VERSION 5.8 ;
BUSBITCHARS "[]" ;
DIVIDERCHAR "/" ;
UNITS
    DATABASE MICRONS 1000 ;
END UNITS

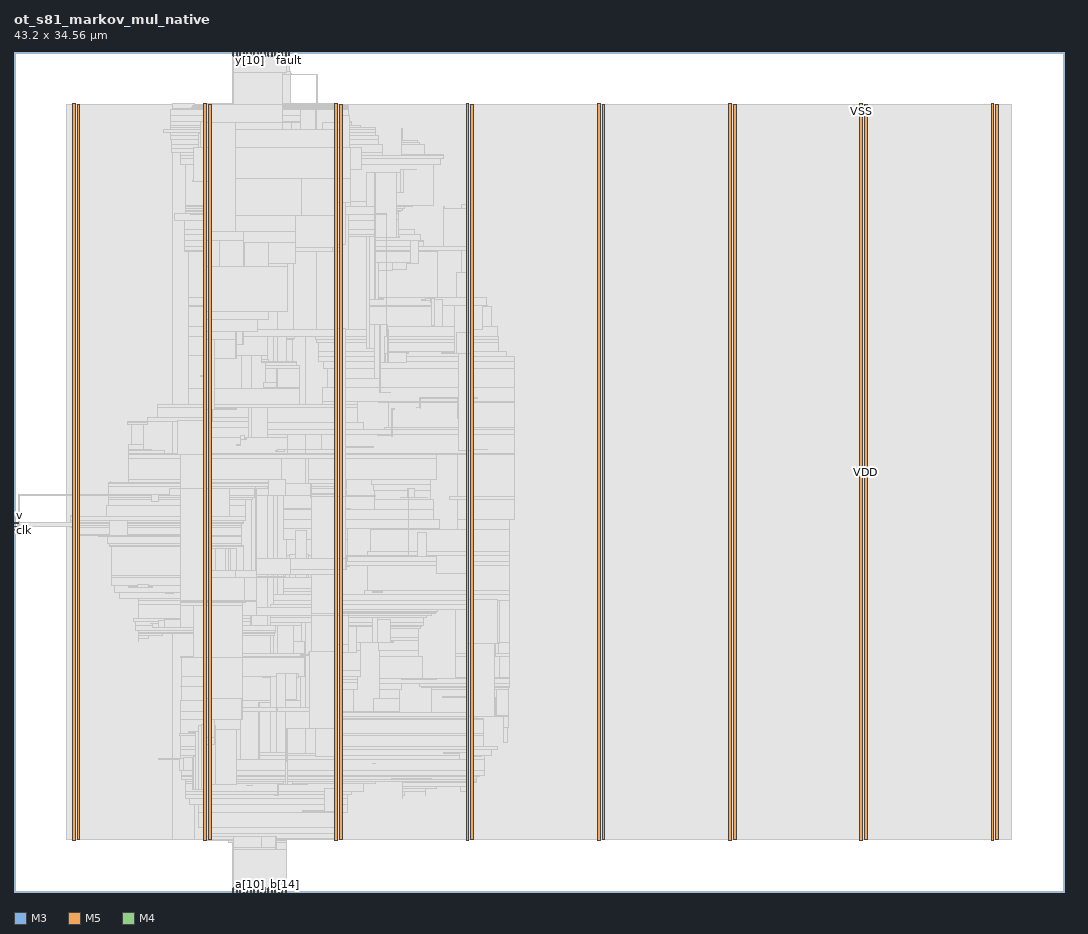
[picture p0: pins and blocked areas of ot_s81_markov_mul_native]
MACRO ot_s81_markov_mul_native
  FOREIGN ot_s81_markov_mul_native 0 0 ;
  CLASS BLOCK ;
  SIZE 43.2 BY 34.56 ;
  PIN a[0]
    DIRECTION INPUT ;
    USE SIGNAL ;
    PORT
      LAYER M3 ;
        RECT  9 0 9.018 0.144 ;
    END
  END a[0]
  PIN a[10]
    DIRECTION INPUT ;
    USE SIGNAL ;
    PORT
      LAYER M3 ;
        RECT  9.72 0 9.738 0.144 ;
    END
  END a[10]
  PIN a[11]
    DIRECTION INPUT ;
    USE SIGNAL ;
    PORT
      LAYER M5 ;
        RECT  9.744 0 9.768 0.192 ;
    END
  END a[11]
  PIN a[12]
    DIRECTION INPUT ;
    USE SIGNAL ;
    PORT
      LAYER M3 ;
        RECT  9.864 0 9.882 0.144 ;
    END
  END a[12]
  PIN a[13]
    DIRECTION INPUT ;
    USE SIGNAL ;
    PORT
      LAYER M5 ;
        RECT  9.888 0 9.912 0.192 ;
    END
  END a[13]
  PIN a[14]
    DIRECTION INPUT ;
    USE SIGNAL ;
    PORT
      LAYER M3 ;
        RECT  10.008 0 10.026 0.144 ;
    END
  END a[14]
  PIN a[15]
    DIRECTION INPUT ;
    USE SIGNAL ;
    PORT
      LAYER M5 ;
        RECT  10.032 0 10.056 0.192 ;
    END
  END a[15]
  PIN a[1]
    DIRECTION INPUT ;
    USE SIGNAL ;
    PORT
      LAYER M5 ;
        RECT  9.024 0 9.048 0.192 ;
    END
  END a[1]
  PIN a[2]
    DIRECTION INPUT ;
    USE SIGNAL ;
    PORT
      LAYER M3 ;
        RECT  9.144 0 9.162 0.144 ;
    END
  END a[2]
  PIN a[3]
    DIRECTION INPUT ;
    USE SIGNAL ;
    PORT
      LAYER M5 ;
        RECT  9.168 0 9.192 0.192 ;
    END
  END a[3]
  PIN a[4]
    DIRECTION INPUT ;
    USE SIGNAL ;
    PORT
      LAYER M3 ;
        RECT  9.288 0 9.306 0.144 ;
    END
  END a[4]
  PIN a[5]
    DIRECTION INPUT ;
    USE SIGNAL ;
    PORT
      LAYER M5 ;
        RECT  9.312 0 9.336 0.192 ;
    END
  END a[5]
  PIN a[6]
    DIRECTION INPUT ;
    USE SIGNAL ;
    PORT
      LAYER M3 ;
        RECT  9.432 0 9.45 0.144 ;
    END
  END a[6]
  PIN a[7]
    DIRECTION INPUT ;
    USE SIGNAL ;
    PORT
      LAYER M5 ;
        RECT  9.456 0 9.48 0.192 ;
    END
  END a[7]
  PIN a[8]
    DIRECTION INPUT ;
    USE SIGNAL ;
    PORT
      LAYER M3 ;
        RECT  9.576 0 9.594 0.144 ;
    END
  END a[8]
  PIN a[9]
    DIRECTION INPUT ;
    USE SIGNAL ;
    PORT
      LAYER M5 ;
        RECT  9.6 0 9.624 0.192 ;
    END
  END a[9]
  PIN b[0]
    DIRECTION INPUT ;
    USE SIGNAL ;
    PORT
      LAYER M3 ;
        RECT  10.152 0 10.17 0.144 ;
    END
  END b[0]
  PIN b[10]
    DIRECTION INPUT ;
    USE SIGNAL ;
    PORT
      LAYER M3 ;
        RECT  10.872 0 10.89 0.144 ;
    END
  END b[10]
  PIN b[11]
    DIRECTION INPUT ;
    USE SIGNAL ;
    PORT
      LAYER M5 ;
        RECT  10.896 0 10.92 0.192 ;
    END
  END b[11]
  PIN b[12]
    DIRECTION INPUT ;
    USE SIGNAL ;
    PORT
      LAYER M3 ;
        RECT  11.016 0 11.034 0.144 ;
    END
  END b[12]
  PIN b[13]
    DIRECTION INPUT ;
    USE SIGNAL ;
    PORT
      LAYER M5 ;
        RECT  11.04 0 11.064 0.192 ;
    END
  END b[13]
  PIN b[14]
    DIRECTION INPUT ;
    USE SIGNAL ;
    PORT
      LAYER M3 ;
        RECT  11.16 0 11.178 0.144 ;
    END
  END b[14]
  PIN b[15]
    DIRECTION INPUT ;
    USE SIGNAL ;
    PORT
      LAYER M5 ;
        RECT  11.184 0 11.208 0.192 ;
    END
  END b[15]
  PIN b[1]
    DIRECTION INPUT ;
    USE SIGNAL ;
    PORT
      LAYER M5 ;
        RECT  10.176 0 10.2 0.192 ;
    END
  END b[1]
  PIN b[2]
    DIRECTION INPUT ;
    USE SIGNAL ;
    PORT
      LAYER M3 ;
        RECT  10.296 0 10.314 0.144 ;
    END
  END b[2]
  PIN b[3]
    DIRECTION INPUT ;
    USE SIGNAL ;
    PORT
      LAYER M5 ;
        RECT  10.32 0 10.344 0.192 ;
    END
  END b[3]
  PIN b[4]
    DIRECTION INPUT ;
    USE SIGNAL ;
    PORT
      LAYER M3 ;
        RECT  10.44 0 10.458 0.144 ;
    END
  END b[4]
  PIN b[5]
    DIRECTION INPUT ;
    USE SIGNAL ;
    PORT
      LAYER M5 ;
        RECT  10.464 0 10.488 0.192 ;
    END
  END b[5]
  PIN b[6]
    DIRECTION INPUT ;
    USE SIGNAL ;
    PORT
      LAYER M3 ;
        RECT  10.584 0 10.602 0.144 ;
    END
  END b[6]
  PIN b[7]
    DIRECTION INPUT ;
    USE SIGNAL ;
    PORT
      LAYER M5 ;
        RECT  10.608 0 10.632 0.192 ;
    END
  END b[7]
  PIN b[8]
    DIRECTION INPUT ;
    USE SIGNAL ;
    PORT
      LAYER M3 ;
        RECT  10.728 0 10.746 0.144 ;
    END
  END b[8]
  PIN b[9]
    DIRECTION INPUT ;
    USE SIGNAL ;
    PORT
      LAYER M5 ;
        RECT  10.752 0 10.776 0.192 ;
    END
  END b[9]
  PIN clk
    DIRECTION INPUT ;
    USE SIGNAL ;
    PORT
      LAYER M4 ;
        RECT  0 14.88 0.192 14.904 ;
    END
  END clk
  PIN fault
    DIRECTION OUTPUT ;
    USE SIGNAL ;
    PORT
      LAYER M3 ;
        RECT  11.304 34.416 11.322 34.56 ;
    END
  END fault
  PIN rst_n
    DIRECTION INPUT ;
    USE SIGNAL ;
    PORT
      LAYER M4 ;
        RECT  0 15.024 0.192 15.048 ;
    END
  END rst_n
  PIN v
    DIRECTION INPUT ;
    USE SIGNAL ;
    PORT
      LAYER M4 ;
        RECT  0 15.168 0.192 15.192 ;
    END
  END v
  PIN y[0]
    DIRECTION OUTPUT ;
    USE SIGNAL ;
    PORT
      LAYER M3 ;
        RECT  9 34.416 9.018 34.56 ;
    END
  END y[0]
  PIN y[10]
    DIRECTION OUTPUT ;
    USE SIGNAL ;
    PORT
      LAYER M3 ;
        RECT  9.72 34.416 9.738 34.56 ;
    END
  END y[10]
  PIN y[11]
    DIRECTION OUTPUT ;
    USE SIGNAL ;
    PORT
      LAYER M5 ;
        RECT  9.744 34.368 9.768 34.56 ;
    END
  END y[11]
  PIN y[12]
    DIRECTION OUTPUT ;
    USE SIGNAL ;
    PORT
      LAYER M3 ;
        RECT  9.864 34.416 9.882 34.56 ;
    END
  END y[12]
  PIN y[13]
    DIRECTION OUTPUT ;
    USE SIGNAL ;
    PORT
      LAYER M5 ;
        RECT  9.888 34.368 9.912 34.56 ;
    END
  END y[13]
  PIN y[14]
    DIRECTION OUTPUT ;
    USE SIGNAL ;
    PORT
      LAYER M3 ;
        RECT  10.008 34.416 10.026 34.56 ;
    END
  END y[14]
  PIN y[15]
    DIRECTION OUTPUT ;
    USE SIGNAL ;
    PORT
      LAYER M5 ;
        RECT  10.032 34.368 10.056 34.56 ;
    END
  END y[15]
  PIN y[16]
    DIRECTION OUTPUT ;
    USE SIGNAL ;
    PORT
      LAYER M3 ;
        RECT  10.152 34.416 10.17 34.56 ;
    END
  END y[16]
  PIN y[17]
    DIRECTION OUTPUT ;
    USE SIGNAL ;
    PORT
      LAYER M5 ;
        RECT  10.176 34.368 10.2 34.56 ;
    END
  END y[17]
  PIN y[18]
    DIRECTION OUTPUT ;
    USE SIGNAL ;
    PORT
      LAYER M3 ;
        RECT  10.296 34.416 10.314 34.56 ;
    END
  END y[18]
  PIN y[19]
    DIRECTION OUTPUT ;
    USE SIGNAL ;
    PORT
      LAYER M5 ;
        RECT  10.32 34.368 10.344 34.56 ;
    END
  END y[19]
  PIN y[1]
    DIRECTION OUTPUT ;
    USE SIGNAL ;
    PORT
      LAYER M5 ;
        RECT  9.024 34.368 9.048 34.56 ;
    END
  END y[1]
  PIN y[20]
    DIRECTION OUTPUT ;
    USE SIGNAL ;
    PORT
      LAYER M3 ;
        RECT  10.44 34.416 10.458 34.56 ;
    END
  END y[20]
  PIN y[21]
    DIRECTION OUTPUT ;
    USE SIGNAL ;
    PORT
      LAYER M5 ;
        RECT  10.464 34.368 10.488 34.56 ;
    END
  END y[21]
  PIN y[22]
    DIRECTION OUTPUT ;
    USE SIGNAL ;
    PORT
      LAYER M3 ;
        RECT  10.584 34.416 10.602 34.56 ;
    END
  END y[22]
  PIN y[23]
    DIRECTION OUTPUT ;
    USE SIGNAL ;
    PORT
      LAYER M5 ;
        RECT  10.608 34.368 10.632 34.56 ;
    END
  END y[23]
  PIN y[24]
    DIRECTION OUTPUT ;
    USE SIGNAL ;
    PORT
      LAYER M3 ;
        RECT  10.728 34.416 10.746 34.56 ;
    END
  END y[24]
  PIN y[25]
    DIRECTION OUTPUT ;
    USE SIGNAL ;
    PORT
      LAYER M5 ;
        RECT  10.752 34.368 10.776 34.56 ;
    END
  END y[25]
  PIN y[26]
    DIRECTION OUTPUT ;
    USE SIGNAL ;
    PORT
      LAYER M3 ;
        RECT  10.872 34.416 10.89 34.56 ;
    END
  END y[26]
  PIN y[27]
    DIRECTION OUTPUT ;
    USE SIGNAL ;
    PORT
      LAYER M5 ;
        RECT  10.896 34.368 10.92 34.56 ;
    END
  END y[27]
  PIN y[28]
    DIRECTION OUTPUT ;
    USE SIGNAL ;
    PORT
      LAYER M3 ;
        RECT  11.016 34.416 11.034 34.56 ;
    END
  END y[28]
  PIN y[29]
    DIRECTION OUTPUT ;
    USE SIGNAL ;
    PORT
      LAYER M5 ;
        RECT  11.04 34.368 11.064 34.56 ;
    END
  END y[29]
  PIN y[2]
    DIRECTION OUTPUT ;
    USE SIGNAL ;
    PORT
      LAYER M3 ;
        RECT  9.144 34.416 9.162 34.56 ;
    END
  END y[2]
  PIN y[30]
    DIRECTION OUTPUT ;
    USE SIGNAL ;
    PORT
      LAYER M3 ;
        RECT  11.16 34.416 11.178 34.56 ;
    END
  END y[30]
  PIN y[31]
    DIRECTION OUTPUT ;
    USE SIGNAL ;
    PORT
      LAYER M5 ;
        RECT  11.184 34.368 11.208 34.56 ;
    END
  END y[31]
  PIN y[3]
    DIRECTION OUTPUT ;
    USE SIGNAL ;
    PORT
      LAYER M5 ;
        RECT  9.168 34.368 9.192 34.56 ;
    END
  END y[3]
  PIN y[4]
    DIRECTION OUTPUT ;
    USE SIGNAL ;
    PORT
      LAYER M3 ;
        RECT  9.288 34.416 9.306 34.56 ;
    END
  END y[4]
  PIN y[5]
    DIRECTION OUTPUT ;
    USE SIGNAL ;
    PORT
      LAYER M5 ;
        RECT  9.312 34.368 9.336 34.56 ;
    END
  END y[5]
  PIN y[6]
    DIRECTION OUTPUT ;
    USE SIGNAL ;
    PORT
      LAYER M3 ;
        RECT  9.432 34.416 9.45 34.56 ;
    END
  END y[6]
  PIN y[7]
    DIRECTION OUTPUT ;
    USE SIGNAL ;
    PORT
      LAYER M5 ;
        RECT  9.456 34.368 9.48 34.56 ;
    END
  END y[7]
  PIN y[8]
    DIRECTION OUTPUT ;
    USE SIGNAL ;
    PORT
      LAYER M3 ;
        RECT  9.576 34.416 9.594 34.56 ;
    END
  END y[8]
  PIN y[9]
    DIRECTION OUTPUT ;
    USE SIGNAL ;
    PORT
      LAYER M5 ;
        RECT  9.6 34.368 9.624 34.56 ;
    END
  END y[9]
  PIN VDD
    DIRECTION INOUT ;
    USE POWER ;
    PORT
      LAYER M5 ;
        RECT  40.392 2.151 40.512 32.409 ;
        RECT  34.992 2.151 35.112 32.409 ;
        RECT  29.592 2.151 29.712 32.409 ;
        RECT  24.192 2.151 24.312 32.409 ;
        RECT  18.792 2.151 18.912 32.409 ;
        RECT  13.392 2.151 13.512 32.409 ;
        RECT  7.992 2.151 8.112 32.409 ;
        RECT  2.592 2.151 2.712 32.409 ;
    END
  END VDD
  PIN VSS
    DIRECTION INOUT ;
    USE GROUND ;
    PORT
      LAYER M5 ;
        RECT  40.2 2.137 40.32 32.423 ;
        RECT  34.8 2.137 34.92 32.423 ;
        RECT  29.4 2.137 29.52 32.423 ;
        RECT  24 2.137 24.12 32.423 ;
        RECT  18.6 2.137 18.72 32.423 ;
        RECT  13.2 2.137 13.32 32.423 ;
        RECT  7.8 2.137 7.92 32.423 ;
        RECT  2.4 2.137 2.52 32.423 ;
    END
  END VSS
  # OT_OBS_CLOSED layer=M5 d_um=1.536 added=25
  OBS
    LAYER RVTN ;
     RECT  2.16 2.16 41.04 2.295 ;
     RECT  2.16 2.565 41.04 2.835 ;
     RECT  2.16 3.105 41.04 3.375 ;
     RECT  2.16 3.645 41.04 3.915 ;
     RECT  2.16 4.185 41.04 4.455 ;
     RECT  2.16 4.725 41.04 4.995 ;
     RECT  2.16 5.265 41.04 5.535 ;
     RECT  2.16 5.805 41.04 6.075 ;
     RECT  2.16 6.345 41.04 6.615 ;
     RECT  2.16 6.885 41.04 7.155 ;
     RECT  2.16 7.425 41.04 7.695 ;
     RECT  2.16 7.965 41.04 8.235 ;
     RECT  2.16 8.505 41.04 8.775 ;
     RECT  2.16 9.045 41.04 9.315 ;
     RECT  2.16 9.585 41.04 9.855 ;
     RECT  2.16 10.125 41.04 10.395 ;
     RECT  2.16 10.665 41.04 10.935 ;
     RECT  2.16 11.205 41.04 11.475 ;
     RECT  2.16 11.745 41.04 12.015 ;
     RECT  2.16 12.285 41.04 12.555 ;
     RECT  2.16 12.825 41.04 13.095 ;
     RECT  2.16 13.365 41.04 13.635 ;
     RECT  2.16 13.905 41.04 14.175 ;
     RECT  2.16 14.445 41.04 14.715 ;
     RECT  2.16 14.985 41.04 15.255 ;
     RECT  2.16 15.525 41.04 15.795 ;
     RECT  2.16 16.065 41.04 16.335 ;
     RECT  2.16 16.605 41.04 16.875 ;
     RECT  2.16 17.145 41.04 17.415 ;
     RECT  2.16 17.685 41.04 17.955 ;
     RECT  2.16 18.225 41.04 18.495 ;
     RECT  2.16 18.765 41.04 19.035 ;
     RECT  2.16 19.305 41.04 19.575 ;
     RECT  2.16 19.845 41.04 20.115 ;
     RECT  2.16 20.385 41.04 20.655 ;
     RECT  2.16 20.925 41.04 21.195 ;
     RECT  2.16 21.465 41.04 21.735 ;
     RECT  2.16 22.005 41.04 22.275 ;
     RECT  2.16 22.545 41.04 22.815 ;
     RECT  2.16 23.085 41.04 23.355 ;
     RECT  2.16 23.625 41.04 23.895 ;
     RECT  2.16 24.165 41.04 24.435 ;
     RECT  2.16 24.705 41.04 24.975 ;
     RECT  2.16 25.245 41.04 25.515 ;
     RECT  2.16 25.785 41.04 26.055 ;
     RECT  2.16 26.325 41.04 26.595 ;
     RECT  2.16 26.865 41.04 27.135 ;
     RECT  2.16 27.405 41.04 27.675 ;
     RECT  2.16 27.945 41.04 28.215 ;
     RECT  2.16 28.485 41.04 28.755 ;
     RECT  2.16 29.025 41.04 29.295 ;
     RECT  2.16 29.565 41.04 29.835 ;
     RECT  2.16 30.105 41.04 30.375 ;
     RECT  2.16 30.645 41.04 30.915 ;
     RECT  2.16 31.185 41.04 31.455 ;
     RECT  2.16 31.725 41.04 31.995 ;
     RECT  2.16 32.265 41.04 32.4 ;
    LAYER RVTP ;
     RECT  2.16 2.295 41.04 2.565 ;
     RECT  2.16 2.835 41.04 3.105 ;
     RECT  2.16 3.375 41.04 3.645 ;
     RECT  2.16 3.915 41.04 4.185 ;
     RECT  2.16 4.455 41.04 4.725 ;
     RECT  2.16 4.995 41.04 5.265 ;
     RECT  2.16 5.535 41.04 5.805 ;
     RECT  2.16 6.075 41.04 6.345 ;
     RECT  2.16 6.615 41.04 6.885 ;
     RECT  2.16 7.155 41.04 7.425 ;
     RECT  2.16 7.695 41.04 7.965 ;
     RECT  2.16 8.235 41.04 8.505 ;
     RECT  2.16 8.775 41.04 9.045 ;
     RECT  2.16 9.315 41.04 9.585 ;
     RECT  2.16 9.855 41.04 10.125 ;
     RECT  2.16 10.395 41.04 10.665 ;
     RECT  2.16 10.935 41.04 11.205 ;
     RECT  2.16 11.475 41.04 11.745 ;
     RECT  2.16 12.015 41.04 12.285 ;
     RECT  2.16 12.555 41.04 12.825 ;
     RECT  2.16 13.095 41.04 13.365 ;
     RECT  2.16 13.635 41.04 13.905 ;
     RECT  2.16 14.175 41.04 14.445 ;
     RECT  2.16 14.715 41.04 14.985 ;
     RECT  2.16 15.255 41.04 15.525 ;
     RECT  2.16 15.795 41.04 16.065 ;
     RECT  2.16 16.335 41.04 16.605 ;
     RECT  2.16 16.875 41.04 17.145 ;
     RECT  2.16 17.415 41.04 17.685 ;
     RECT  2.16 17.955 41.04 18.225 ;
     RECT  2.16 18.495 41.04 18.765 ;
     RECT  2.16 19.035 41.04 19.305 ;
     RECT  2.16 19.575 41.04 19.845 ;
     RECT  2.16 20.115 41.04 20.385 ;
     RECT  2.16 20.655 41.04 20.925 ;
     RECT  2.16 21.195 41.04 21.465 ;
     RECT  2.16 21.735 41.04 22.005 ;
     RECT  2.16 22.275 41.04 22.545 ;
     RECT  2.16 22.815 41.04 23.085 ;
     RECT  2.16 23.355 41.04 23.625 ;
     RECT  2.16 23.895 41.04 24.165 ;
     RECT  2.16 24.435 41.04 24.705 ;
     RECT  2.16 24.975 41.04 25.245 ;
     RECT  2.16 25.515 41.04 25.785 ;
     RECT  2.16 26.055 41.04 26.325 ;
     RECT  2.16 26.595 41.04 26.865 ;
     RECT  2.16 27.135 41.04 27.405 ;
     RECT  2.16 27.675 41.04 27.945 ;
     RECT  2.16 28.215 41.04 28.485 ;
     RECT  2.16 28.755 41.04 29.025 ;
     RECT  2.16 29.295 41.04 29.565 ;
     RECT  2.16 29.835 41.04 30.105 ;
     RECT  2.16 30.375 41.04 30.645 ;
     RECT  2.16 30.915 41.04 31.185 ;
     RECT  2.16 31.455 41.04 31.725 ;
     RECT  2.16 31.995 41.04 32.265 ;
    LAYER M1 ;
     RECT  2.16 2.151 41.04 32.409 ;
    LAYER M2 ;
     RECT  2.16 2.151 6.511 32.409 ;
     RECT  6.511 2.151 7.439 32.454 ;
     RECT  7.439 2.151 8.131 32.409 ;
     RECT  8.131 2.106 8.815 32.409 ;
     RECT  8.815 2.034 9.311 32.409 ;
     RECT  9.311 2.151 9.751 32.409 ;
     RECT  9.751 2.151 10.427 32.454 ;
     RECT  10.427 2.151 10.687 32.409 ;
     RECT  10.687 1.764 10.823 32.409 ;
     RECT  10.823 2.151 11.983 32.409 ;
     RECT  11.155 33.624 12.479 33.642 ;
     RECT  11.983 2.151 13.163 32.454 ;
     RECT  13.163 2.151 41.04 32.409 ;
    LAYER M3 ;
     RECT  9 0.108 11.178 1.723 ;
     RECT  9 1.723 11.214 2.029 ;
     RECT  8.82 2.029 11.214 2.101 ;
     RECT  8.136 2.101 11.214 2.143 ;
     RECT  7.815 2.143 11.214 2.191 ;
     RECT  13.215 2.143 13.305 2.191 ;
     RECT  2.415 2.143 2.505 2.413 ;
     RECT  7.815 2.191 13.305 2.413 ;
     RECT  18.615 2.143 18.705 2.413 ;
     RECT  24.015 2.143 24.105 2.413 ;
     RECT  29.415 2.143 29.505 2.413 ;
     RECT  34.815 2.143 34.905 2.413 ;
     RECT  40.215 2.143 40.305 2.413 ;
     RECT  7.815 2.413 13.497 2.641 ;
     RECT  7.596 2.641 13.497 3.271 ;
     RECT  7.596 3.271 13.734 3.613 ;
     RECT  7.2 3.613 13.734 3.847 ;
     RECT  15.984 3.847 16.002 3.955 ;
     RECT  7.056 3.847 13.734 3.991 ;
     RECT  7.056 3.991 13.878 4.117 ;
     RECT  15.984 3.955 16.074 4.117 ;
     RECT  16.92 3.955 16.938 4.117 ;
     RECT  18.615 2.413 18.897 4.153 ;
     RECT  15.984 4.117 16.938 4.261 ;
     RECT  15.984 4.261 17.37 4.351 ;
     RECT  18.36 4.153 18.897 4.351 ;
     RECT  7.056 4.117 14.382 4.459 ;
     RECT  15.984 4.351 18.897 4.495 ;
     RECT  7.056 4.459 14.886 4.531 ;
     RECT  15.984 4.495 19.026 4.531 ;
     RECT  7.056 4.531 19.026 4.621 ;
     RECT  6.876 4.621 19.026 4.765 ;
     RECT  6.876 4.765 19.134 4.801 ;
     RECT  6.876 4.801 19.35 4.987 ;
     RECT  6.804 4.987 19.35 5.459 ;
     RECT  5.976 5.467 5.994 5.504 ;
     RECT  6.84 5.459 19.35 5.611 ;
     RECT  6.84 5.611 19.638 5.881 ;
     RECT  6.84 5.881 19.89 5.999 ;
     RECT  6.84 5.999 19.314 6.421 ;
     RECT  6.804 6.421 19.314 6.539 ;
     RECT  20.124 6.151 20.286 6.781 ;
     RECT  6.84 6.539 19.314 7.079 ;
     RECT  12.636 7.079 19.314 7.115 ;
     RECT  12.852 7.115 19.314 7.151 ;
     RECT  12.852 7.151 19.026 7.223 ;
     RECT  20.124 6.781 20.358 7.231 ;
     RECT  19.764 7.231 20.358 7.277 ;
     RECT  13.032 7.223 19.026 7.385 ;
     RECT  6.84 7.079 11.898 7.421 ;
     RECT  13.032 7.385 15.858 7.421 ;
     RECT  6.84 7.421 11.79 7.889 ;
     RECT  14.796 7.421 15.858 7.961 ;
     RECT  13.104 7.421 13.986 8.311 ;
     RECT  15.048 7.961 15.858 8.311 ;
     RECT  17.172 7.385 19.026 8.311 ;
     RECT  19.836 7.277 20.358 8.311 ;
     RECT  17.172 8.311 20.358 8.401 ;
     RECT  16.776 8.401 20.394 8.437 ;
     RECT  15.048 8.311 15.93 8.581 ;
     RECT  16.668 8.437 20.394 8.581 ;
     RECT  13.104 8.311 14.13 8.609 ;
     RECT  13.14 8.609 14.13 8.735 ;
     RECT  15.048 8.581 20.394 8.771 ;
     RECT  18.18 8.771 20.394 8.843 ;
     RECT  6.876 7.889 11.79 8.851 ;
     RECT  13.215 8.735 14.13 8.851 ;
     RECT  13.215 8.851 14.238 9.121 ;
     RECT  6.876 8.851 11.934 9.661 ;
     RECT  6.876 9.661 11.97 9.677 ;
     RECT  15.048 8.771 16.794 9.689 ;
     RECT  18.18 8.843 19.134 9.691 ;
     RECT  19.98 8.843 20.394 9.691 ;
     RECT  7.38 9.677 11.97 9.815 ;
     RECT  18.18 9.691 20.394 9.815 ;
     RECT  13.215 9.121 14.274 9.931 ;
     RECT  15.048 9.689 16.65 9.931 ;
     RECT  19.944 9.815 20.394 10.253 ;
     RECT  11.484 9.815 11.97 10.319 ;
     RECT  12.888 9.931 14.274 10.327 ;
     RECT  15.012 9.931 16.65 10.327 ;
     RECT  5.112 10.291 5.13 10.435 ;
     RECT  12.852 10.327 16.65 10.471 ;
     RECT  5.112 10.435 5.526 10.561 ;
     RECT  7.38 9.815 10.566 10.561 ;
     RECT  5.112 10.561 6.102 10.633 ;
     RECT  7.38 10.561 10.71 10.633 ;
     RECT  5.112 10.633 10.71 10.669 ;
     RECT  5.112 10.669 10.746 10.741 ;
     RECT  12.6 10.471 16.65 10.831 ;
     RECT  12.6 10.831 16.722 10.903 ;
     RECT  5.004 10.741 10.746 10.967 ;
     RECT  10.548 10.967 10.746 10.975 ;
     RECT  11.484 10.319 11.826 10.975 ;
     RECT  12.6 10.903 16.758 10.975 ;
     RECT  10.548 10.975 11.826 11.101 ;
     RECT  12.6 10.975 16.866 11.101 ;
     RECT  5.004 10.967 9.738 11.137 ;
     RECT  4.896 11.137 9.738 11.273 ;
     RECT  10.548 11.101 16.866 11.281 ;
     RECT  10.548 11.281 16.974 11.371 ;
     RECT  10.548 11.371 17.19 11.443 ;
     RECT  10.548 11.443 17.334 11.515 ;
     RECT  10.548 11.515 17.37 11.551 ;
     RECT  10.548 11.551 17.406 11.641 ;
     RECT  18.18 9.815 19.134 11.641 ;
     RECT  10.548 11.641 19.134 11.813 ;
     RECT  5.112 11.273 9.738 11.821 ;
     RECT  5.112 11.821 9.954 11.981 ;
     RECT  10.692 11.813 19.134 11.995 ;
     RECT  19.98 10.253 20.394 11.995 ;
     RECT  5.112 11.981 9.45 12.055 ;
     RECT  10.692 11.995 20.394 12.245 ;
     RECT  4.356 12.055 9.45 12.325 ;
     RECT  11.088 12.245 13.497 12.353 ;
     RECT  14.4 12.245 20.394 12.389 ;
     RECT  11.088 12.353 12.474 12.479 ;
     RECT  4.14 12.325 9.45 12.595 ;
     RECT  3.996 12.595 9.45 12.955 ;
     RECT  3.996 12.955 9.774 13.019 ;
     RECT  13.215 12.353 13.497 13.261 ;
     RECT  11.088 12.479 12.402 13.369 ;
     RECT  11.088 13.369 12.474 13.405 ;
     RECT  13.215 13.261 13.698 13.405 ;
     RECT  11.088 13.405 13.806 13.441 ;
     RECT  14.544 12.389 20.394 13.441 ;
     RECT  11.088 13.441 20.394 13.595 ;
     RECT  11.196 13.595 20.394 13.865 ;
     RECT  14.544 13.865 20.394 14.009 ;
     RECT  3.996 13.019 9.45 14.215 ;
     RECT  3.924 14.215 9.45 14.243 ;
     RECT  3.924 14.243 9.342 14.341 ;
     RECT  11.196 13.865 13.734 14.521 ;
     RECT  3.852 14.341 9.342 14.611 ;
     RECT  2.415 2.413 2.697 14.683 ;
     RECT  3.492 14.611 9.342 14.683 ;
     RECT  14.652 14.009 20.394 14.909 ;
     RECT  11.088 14.521 13.734 14.953 ;
     RECT  14.652 14.909 17.514 14.953 ;
     RECT  2.415 14.683 9.342 15.016 ;
     RECT  2.34 15.016 9.342 15.061 ;
     RECT  2.304 15.061 9.342 15.151 ;
     RECT  2.304 15.151 9.45 15.163 ;
     RECT  2.268 15.163 9.45 15.215 ;
     RECT  2.304 15.215 9.45 15.295 ;
     RECT  11.088 14.953 17.514 15.323 ;
     RECT  18.252 14.909 20.394 15.331 ;
     RECT  2.304 15.295 9.522 15.449 ;
     RECT  2.304 15.449 2.697 15.485 ;
     RECT  11.088 15.323 17.262 15.755 ;
     RECT  11.088 15.755 13.842 15.791 ;
     RECT  3.816 15.449 9.522 15.899 ;
     RECT  14.832 15.755 17.262 16.133 ;
     RECT  3.888 15.899 9.522 16.141 ;
     RECT  18.252 15.331 20.61 16.141 ;
     RECT  3.888 16.141 9.81 16.219 ;
     RECT  17.928 16.141 20.61 16.259 ;
     RECT  11.088 15.791 13.626 16.411 ;
     RECT  14.832 16.133 17.154 16.501 ;
     RECT  10.872 16.411 13.626 16.609 ;
     RECT  3.888 16.219 9.954 16.681 ;
     RECT  10.872 16.609 13.662 16.681 ;
     RECT  14.796 16.501 17.154 16.771 ;
     RECT  3.888 16.681 13.662 16.799 ;
     RECT  3.888 16.799 11.178 16.835 ;
     RECT  3.96 16.835 3.978 16.907 ;
     RECT  12.096 16.799 13.662 16.951 ;
     RECT  14.688 16.771 17.154 16.951 ;
     RECT  4.716 16.835 11.178 16.973 ;
     RECT  4.716 16.973 10.998 17.851 ;
     RECT  12.096 16.951 17.37 17.851 ;
     RECT  4.716 17.851 17.37 17.995 ;
     RECT  18.252 16.259 20.61 17.995 ;
     RECT  4.716 17.995 20.61 18.029 ;
     RECT  7.164 18.029 20.61 18.059 ;
     RECT  4.716 18.029 6.174 18.185 ;
     RECT  4.716 18.185 5.67 18.221 ;
     RECT  4.716 18.221 5.31 18.419 ;
     RECT  7.164 18.059 11.25 18.689 ;
     RECT  10.44 18.689 11.25 18.805 ;
     RECT  11.988 18.059 20.61 18.805 ;
     RECT  10.44 18.805 20.61 19.031 ;
     RECT  15.264 19.031 20.61 19.103 ;
     RECT  7.164 18.689 9.666 19.111 ;
     RECT  4.824 18.419 5.31 19.237 ;
     RECT  4.68 19.237 5.49 19.301 ;
     RECT  10.44 19.031 14.382 19.301 ;
     RECT  5.472 19.301 5.49 19.339 ;
     RECT  6.804 19.111 9.666 19.339 ;
     RECT  4.68 19.301 4.698 19.373 ;
     RECT  5.472 19.339 9.666 19.535 ;
     RECT  5.904 19.535 9.666 19.921 ;
     RECT  10.44 19.301 14.13 19.921 ;
     RECT  5.904 19.921 14.13 20.039 ;
     RECT  5.904 20.039 6.138 20.075 ;
     RECT  6.984 20.039 11.754 20.075 ;
     RECT  15.408 19.103 20.61 20.119 ;
     RECT  12.708 20.039 14.13 20.191 ;
     RECT  14.976 20.119 20.61 20.191 ;
     RECT  7.164 20.075 11.754 20.723 ;
     RECT  10.26 20.723 11.754 20.759 ;
     RECT  12.708 20.191 20.61 20.759 ;
     RECT  10.26 20.759 10.782 20.957 ;
     RECT  10.332 20.957 10.782 21.541 ;
     RECT  11.736 20.759 11.754 21.541 ;
     RECT  12.888 20.759 20.61 21.541 ;
     RECT  10.332 21.541 11.754 21.659 ;
     RECT  10.332 21.659 11.61 21.775 ;
     RECT  12.744 21.541 20.61 21.811 ;
     RECT  10.188 21.775 11.61 21.821 ;
     RECT  10.188 21.821 10.458 21.929 ;
     RECT  12.528 21.811 20.61 22.037 ;
     RECT  7.164 20.723 9.342 22.081 ;
     RECT  10.188 21.929 10.422 22.081 ;
     RECT  12.528 22.037 20.25 22.235 ;
     RECT  12.528 22.235 19.926 22.621 ;
     RECT  11.196 21.821 11.466 22.711 ;
     RECT  12.456 22.621 19.926 22.747 ;
     RECT  11.196 22.711 11.502 22.783 ;
     RECT  12.384 22.747 19.926 22.847 ;
     RECT  7.164 22.081 10.422 22.855 ;
     RECT  11.196 22.783 11.538 22.855 ;
     RECT  12.384 22.847 19.89 22.855 ;
     RECT  7.164 22.855 19.89 23.279 ;
     RECT  7.164 23.279 19.638 24.089 ;
     RECT  7.164 24.089 19.458 24.125 ;
     RECT  7.164 24.125 19.422 24.467 ;
     RECT  18.216 24.467 18.897 25.475 ;
     RECT  7.164 24.467 17.406 26.365 ;
     RECT  7.02 26.365 17.406 26.401 ;
     RECT  18.432 25.475 18.897 26.401 ;
     RECT  7.02 26.401 18.897 26.555 ;
     RECT  7.02 26.555 16.83 26.825 ;
     RECT  7.02 26.825 16.722 27.059 ;
     RECT  7.02 27.059 16.47 27.239 ;
     RECT  7.02 27.239 15.822 27.607 ;
     RECT  6.624 27.607 15.822 27.905 ;
     RECT  7.056 27.905 15.822 27.985 ;
     RECT  7.056 27.985 15.894 28.021 ;
     RECT  7.056 28.021 16.002 28.111 ;
     RECT  17.676 26.555 18.897 28.139 ;
     RECT  7.056 28.111 16.074 28.183 ;
     RECT  17.676 28.139 17.694 28.211 ;
     RECT  7.056 28.183 16.398 28.255 ;
     RECT  18.432 28.139 18.897 28.283 ;
     RECT  7.056 28.255 17.262 29.911 ;
     RECT  6.84 29.911 17.55 30.181 ;
     RECT  6.84 30.181 17.658 30.299 ;
     RECT  15.948 30.299 17.658 30.335 ;
     RECT  6.84 30.299 15.174 30.415 ;
     RECT  6.48 30.415 15.174 30.749 ;
     RECT  15.948 30.335 16.902 30.749 ;
     RECT  15.948 30.749 16.686 30.839 ;
     RECT  15.948 30.839 16.614 30.911 ;
     RECT  6.48 30.749 14.994 30.955 ;
     RECT  6.444 30.955 14.994 31.145 ;
     RECT  6.444 31.145 14.886 31.261 ;
     RECT  6.156 31.261 14.886 31.379 ;
     RECT  15.948 30.911 15.966 31.415 ;
     RECT  6.444 31.379 14.886 31.451 ;
     RECT  6.444 31.451 14.274 31.523 ;
     RECT  6.444 31.523 13.878 31.709 ;
     RECT  6.444 31.709 13.806 31.949 ;
     RECT  2.415 15.485 2.697 32.147 ;
     RECT  18.615 28.283 18.897 32.147 ;
     RECT  24.015 2.413 24.297 32.147 ;
     RECT  29.415 2.413 29.697 32.147 ;
     RECT  34.815 2.413 35.097 32.147 ;
     RECT  40.215 2.413 40.497 32.147 ;
     RECT  6.444 31.949 13.77 32.189 ;
     RECT  6.516 32.189 13.77 32.225 ;
     RECT  7.308 32.225 13.77 32.261 ;
     RECT  7.344 32.261 13.77 32.333 ;
     RECT  7.344 32.333 7.974 32.369 ;
     RECT  8.856 32.333 13.77 32.369 ;
     RECT  2.415 32.147 2.505 32.417 ;
     RECT  7.416 32.369 7.905 32.417 ;
     RECT  9 32.369 13.305 32.417 ;
     RECT  18.615 32.147 18.705 32.417 ;
     RECT  24.015 32.147 24.105 32.417 ;
     RECT  29.415 32.147 29.505 32.417 ;
     RECT  34.815 32.147 34.905 32.417 ;
     RECT  40.215 32.147 40.305 32.417 ;
     RECT  6.516 32.225 6.534 32.459 ;
     RECT  7.416 32.417 7.434 32.459 ;
     RECT  9 32.417 13.158 32.459 ;
     RECT  12.456 32.459 12.474 33.647 ;
     RECT  9 32.459 11.394 33.677 ;
     RECT  9 33.677 11.358 33.773 ;
     RECT  9 33.773 11.322 34.428 ;
    LAYER M4 ;
     RECT  0.156 14.88 0.227 15.192 ;
     RECT  0.227 15.024 2.408 15.192 ;
     RECT  0.181 16.32 2.408 16.344 ;
     RECT  2.408 2.148 2.512 32.412 ;
     RECT  2.512 2.418 2.704 32.142 ;
     RECT  2.704 14.688 3.949 14.712 ;
     RECT  3.949 14.688 4.673 15.288 ;
     RECT  4.705 12.528 5.101 12.552 ;
     RECT  5.101 12.528 5.537 12.648 ;
     RECT  2.704 16.32 5.677 16.344 ;
     RECT  5.605 11.04 5.713 11.064 ;
     RECT  5.537 12.528 5.717 12.552 ;
     RECT  5.677 16.08 5.933 16.344 ;
     RECT  5.713 10.896 5.965 11.064 ;
     RECT  5.965 10.896 6.181 11.16 ;
     RECT  5.933 16.32 6.397 16.344 ;
     RECT  6.217 12.288 6.545 12.312 ;
     RECT  5.965 5.472 6.793 5.496 ;
     RECT  6.181 10.896 6.853 11.208 ;
     RECT  6.793 4.992 6.973 5.496 ;
     RECT  6.973 4.992 7.333 5.544 ;
     RECT  7.333 4.224 7.369 5.544 ;
     RECT  6.865 9.648 7.381 9.672 ;
     RECT  6.853 10.896 7.381 11.832 ;
     RECT  6.469 30.576 7.381 30.6 ;
     RECT  7.369 4.224 7.477 5.592 ;
     RECT  7.189 6.576 7.477 6.6 ;
     RECT  7.477 4.224 7.585 6.6 ;
     RECT  7.381 30.384 7.585 30.6 ;
     RECT  7.585 30.384 7.657 31.224 ;
     RECT  7.585 4.224 7.729 6.84 ;
     RECT  7.729 4.224 7.808 6.888 ;
     RECT  6.865 8.448 7.808 8.472 ;
     RECT  7.381 9.648 7.808 11.832 ;
     RECT  4.673 14.688 7.808 14.712 ;
     RECT  6.397 16.32 7.808 16.584 ;
     RECT  6.677 18 7.808 18.024 ;
     RECT  4.669 19.344 7.808 19.368 ;
     RECT  7.657 21.216 7.808 21.24 ;
     RECT  7.261 27.888 7.808 27.912 ;
     RECT  7.343 29.232 7.808 29.256 ;
     RECT  7.657 30.384 7.808 31.704 ;
     RECT  7.808 2.148 7.912 32.412 ;
     RECT  7.912 2.418 8.104 32.142 ;
     RECT  8.104 19.344 8.165 19.896 ;
     RECT  8.104 21.216 8.243 26.808 ;
     RECT  8.104 4.416 8.273 6.84 ;
     RECT  8.104 7.968 8.309 14.136 ;
     RECT  8.104 27.888 8.381 29.256 ;
     RECT  8.309 7.968 8.641 7.992 ;
     RECT  8.309 9.12 8.705 14.136 ;
     RECT  8.705 9.936 8.819 14.136 ;
     RECT  8.381 28.752 8.849 29.256 ;
     RECT  8.104 15.456 8.885 16.584 ;
     RECT  8.819 10.848 8.921 14.136 ;
     RECT  8.849 28.752 9.029 28.776 ;
     RECT  8.243 21.936 9.109 26.808 ;
     RECT  9.025 0.24 9.125 0.264 ;
     RECT  8.273 4.416 9.137 6.696 ;
     RECT  8.165 19.872 9.137 19.896 ;
     RECT  9.109 21.936 9.137 27.336 ;
     RECT  8.921 12.96 9.155 14.136 ;
     RECT  8.104 30.24 9.169 31.896 ;
     RECT  9.155 14.112 9.173 14.136 ;
     RECT  9.125 0.24 9.209 0.6 ;
     RECT  8.921 10.848 9.281 11.976 ;
     RECT  9.157 33.648 9.301 33.672 ;
     RECT  9.137 5.472 9.308 6.696 ;
     RECT  8.917 2.256 9.313 2.28 ;
     RECT  9.169 18.384 9.313 18.408 ;
     RECT  9.313 18.384 9.317 18.792 ;
     RECT  9.209 0.24 9.349 0.264 ;
     RECT  9.349 0.192 9.35 0.264 ;
     RECT  9.169 30.24 9.385 32.52 ;
     RECT  9.281 10.992 9.395 11.976 ;
     RECT  9.137 22.512 9.404 27.336 ;
     RECT  9.404 22.512 9.425 28.488 ;
     RECT  9.385 29.76 9.493 32.52 ;
     RECT  9.301 33.648 9.493 33.72 ;
     RECT  9.317 18.624 9.497 18.792 ;
     RECT  9.497 18.624 9.569 18.648 ;
     RECT  9.493 29.76 9.635 33.72 ;
     RECT  9.635 29.76 9.713 32.52 ;
     RECT  9.565 4.368 9.821 4.392 ;
     RECT  8.885 16.32 9.884 16.584 ;
     RECT  9.395 11.376 9.971 11.976 ;
     RECT  9.884 16.224 9.971 16.584 ;
     RECT  9.635 33.648 9.973 33.72 ;
     RECT  9.425 23.088 10.019 28.488 ;
     RECT  9.308 5.472 10.069 7.56 ;
     RECT  9.713 30.768 10.108 32.52 ;
     RECT  10.069 5.472 10.109 7.8 ;
     RECT  9.713 29.76 10.109 29.784 ;
     RECT  9.971 16.32 10.465 16.584 ;
     RECT  9.35 0.192 10.505 0.216 ;
     RECT  10.109 5.76 10.537 7.8 ;
     RECT  10.213 8.832 10.537 8.856 ;
     RECT  10.108 30.768 10.721 31.944 ;
     RECT  9.313 1.728 10.787 2.28 ;
     RECT  10.721 30.768 10.787 31.704 ;
     RECT  10.537 5.76 10.789 8.856 ;
     RECT  10.019 23.136 10.825 28.488 ;
     RECT  10.717 3.984 10.861 4.008 ;
     RECT  10.753 18.144 10.861 18.168 ;
     RECT  10.787 30.768 10.861 31.656 ;
     RECT  10.861 3.984 10.865 4.44 ;
     RECT  10.825 0.576 10.931 0.6 ;
     RECT  9.973 33.648 11.029 33.768 ;
     RECT  10.865 4.416 11.077 4.44 ;
     RECT  10.861 18.144 11.117 18.216 ;
     RECT  11.029 33.648 11.117 33.816 ;
     RECT  11.077 4.416 11.173 4.536 ;
     RECT  10.789 5.76 11.173 9 ;
     RECT  9.155 12.96 11.185 12.984 ;
     RECT  11.173 4.416 11.189 9 ;
     RECT  10.465 16.32 11.189 16.968 ;
     RECT  10.787 1.728 11.225 1.752 ;
     RECT  11.189 4.416 11.26 6.888 ;
     RECT  11.185 12.96 11.329 13.704 ;
     RECT  11.117 33.648 11.369 33.768 ;
     RECT  10.861 30.048 11.405 31.656 ;
     RECT  11.369 33.648 11.405 33.672 ;
     RECT  11.26 4.416 11.441 4.536 ;
     RECT  10.825 23.136 11.509 28.968 ;
     RECT  11.329 12.96 11.581 13.896 ;
     RECT  11.189 7.92 11.621 9 ;
     RECT  10.177 21.792 11.621 21.816 ;
     RECT  11.621 8.832 11.693 9 ;
     RECT  11.405 30.72 11.797 31.656 ;
     RECT  11.26 5.712 11.981 6.888 ;
     RECT  11.581 12.96 12.053 14.856 ;
     RECT  11.441 4.416 12.089 4.44 ;
     RECT  12.053 12.96 12.125 13.896 ;
     RECT  11.797 9.744 12.133 9.768 ;
     RECT  12.133 9.744 12.179 9.864 ;
     RECT  11.189 16.32 12.188 16.824 ;
     RECT  12.188 16.224 12.233 16.824 ;
     RECT  11.981 5.712 12.409 6.792 ;
     RECT  11.797 30.72 12.409 32.184 ;
     RECT  11.509 23.136 12.445 29.496 ;
     RECT  12.409 30.576 12.445 32.184 ;
     RECT  11.117 18.192 12.661 18.216 ;
     RECT  11.869 3.312 12.769 3.336 ;
     RECT  12.769 3.312 13.208 4.248 ;
     RECT  12.409 5.568 13.208 6.792 ;
     RECT  12.179 9.84 13.208 9.864 ;
     RECT  9.971 11.376 13.208 11.688 ;
     RECT  12.125 12.96 13.208 13.656 ;
     RECT  12.233 16.224 13.208 16.344 ;
     RECT  12.661 18.192 13.208 18.84 ;
     RECT  12.445 23.136 13.208 32.184 ;
     RECT  13.208 2.148 13.312 32.412 ;
     RECT  13.312 2.418 13.504 32.142 ;
     RECT  13.504 13.296 13.667 13.848 ;
     RECT  13.504 16.272 13.681 16.536 ;
     RECT  13.667 13.632 13.709 13.848 ;
     RECT  13.504 9.84 13.763 11.448 ;
     RECT  13.504 23.136 13.781 28.392 ;
     RECT  13.504 29.712 13.817 31.944 ;
     RECT  13.817 31.68 13.889 31.704 ;
     RECT  13.763 9.84 14.105 10.92 ;
     RECT  13.817 29.712 14.285 30.648 ;
     RECT  13.781 23.136 14.497 26.952 ;
     RECT  13.781 28.176 14.497 28.392 ;
     RECT  14.497 22.368 14.645 26.952 ;
     RECT  14.105 10.272 14.749 10.92 ;
     RECT  13.504 18.288 14.789 18.312 ;
     RECT  13.504 21.12 14.821 21.144 ;
     RECT  14.645 22.368 14.821 23.352 ;
     RECT  14.645 24.384 14.821 26.952 ;
     RECT  14.497 28.176 14.821 29.592 ;
     RECT  14.749 5.28 14.861 5.304 ;
     RECT  13.681 16.272 14.861 16.296 ;
     RECT  14.821 24.384 14.861 29.592 ;
     RECT  14.749 10.272 14.969 11.304 ;
     RECT  14.861 24.384 15.005 25.896 ;
     RECT  14.821 21.12 15.037 23.352 ;
     RECT  15.037 20.544 15.077 23.352 ;
     RECT  14.749 12.336 15.149 12.36 ;
     RECT  15.005 24.384 15.221 24.408 ;
     RECT  15.077 21.792 15.373 23.352 ;
     RECT  15.373 21.792 15.395 23.16 ;
     RECT  15.077 20.544 15.473 20.568 ;
     RECT  14.969 10.272 15.509 11.208 ;
     RECT  15.005 25.584 15.581 25.896 ;
     RECT  14.965 18.768 15.587 18.792 ;
     RECT  15.509 10.272 15.617 10.296 ;
     RECT  15.541 19.872 15.653 19.896 ;
     RECT  14.861 26.928 15.725 29.592 ;
     RECT  15.725 26.928 15.833 27.672 ;
     RECT  15.833 26.928 15.869 26.952 ;
     RECT  15.725 28.8 15.901 29.592 ;
     RECT  15.901 28.8 16.013 29.736 ;
     RECT  15.395 21.792 16.157 22.2 ;
     RECT  15.581 25.632 16.157 25.896 ;
     RECT  15.901 16.224 16.181 16.248 ;
     RECT  16.157 22.176 16.229 22.2 ;
     RECT  16.157 25.872 16.297 25.896 ;
     RECT  16.181 16.224 16.481 16.584 ;
     RECT  16.013 29.712 16.553 29.736 ;
     RECT  13.709 13.824 16.585 13.848 ;
     RECT  16.297 25.872 16.661 26.808 ;
     RECT  16.549 19.92 16.693 19.944 ;
     RECT  16.693 19.92 16.739 20.328 ;
     RECT  16.661 26.784 16.841 26.808 ;
     RECT  16.765 24.336 16.945 24.36 ;
     RECT  16.585 13.824 16.985 14.808 ;
     RECT  16.481 16.224 17.021 16.248 ;
     RECT  16.945 24.336 17.125 24.408 ;
     RECT  17.125 24.24 17.161 24.408 ;
     RECT  15.541 4.656 17.165 4.68 ;
     RECT  17.161 23.328 17.305 24.408 ;
     RECT  17.305 23.28 17.309 24.408 ;
     RECT  16.985 13.824 17.377 13.848 ;
     RECT  15.937 8.736 17.381 8.76 ;
     RECT  17.309 23.28 17.633 24.36 ;
     RECT  17.593 22.176 18.133 22.2 ;
     RECT  17.633 23.28 18.133 24.12 ;
     RECT  16.739 20.304 18.236 20.328 ;
     RECT  17.665 5.712 18.313 5.736 ;
     RECT  18.313 5.472 18.608 5.736 ;
     RECT  17.629 8.016 18.608 8.04 ;
     RECT  17.377 13.104 18.608 13.848 ;
     RECT  18.277 18.192 18.608 18.216 ;
     RECT  18.236 19.488 18.608 20.328 ;
     RECT  18.133 22.176 18.608 24.12 ;
     RECT  18.608 2.148 18.712 32.412 ;
     RECT  18.712 2.418 18.904 32.142 ;
     RECT  18.904 20.304 19.073 20.328 ;
     RECT  18.904 5.568 19.253 5.592 ;
     RECT  18.904 23.136 19.289 24.12 ;
     RECT  18.904 18.192 19.469 18.216 ;
     RECT  19.289 24.096 19.469 24.12 ;
     RECT  18.904 9.696 19.801 10.248 ;
     RECT  18.904 7.248 19.804 7.992 ;
     RECT  19.804 7.968 19.865 7.992 ;
     RECT  18.904 12 19.907 12.024 ;
     RECT  19.801 10.224 19.973 10.248 ;
     RECT  24.008 2.148 24.112 32.412 ;
     RECT  24.112 2.418 24.304 32.142 ;
     RECT  29.408 2.148 29.512 32.412 ;
     RECT  29.512 2.418 29.704 32.142 ;
     RECT  34.808 2.148 34.912 32.412 ;
     RECT  34.912 2.418 35.104 32.142 ;
     RECT  40.208 2.148 40.312 32.412 ;
     RECT  40.312 2.418 40.504 32.142 ;
    LAYER M5 ;
     RECT  9.024 0.144 11.208 1.763 ;
     RECT  9.024 1.763 10.776 1.811 ;
     RECT  2.4 2.137 2.52 2.151 ;
     RECT  7.8 2.137 7.92 2.151 ;
     RECT  9.024 1.811 9.048 2.151 ;
     RECT  13.2 2.137 13.32 2.151 ;
     RECT  18.6 2.137 18.72 2.151 ;
     RECT  24 2.137 24.12 2.151 ;
     RECT  29.4 2.137 29.52 2.151 ;
     RECT  34.8 2.137 34.92 2.151 ;
     RECT  40.2 2.137 40.32 2.151 ;
     RECT  7.8 2.151 9.048 2.291 ;
     RECT  10.176 1.811 10.776 2.291 ;
     RECT  7.8 2.291 8.112 6.085 ;
     RECT  11.184 5.365 11.208 6.275 ;
     RECT  7.8 6.085 8.232 6.371 ;
     RECT  18.6 2.151 18.912 7.237 ;
     RECT  10.8 7.429 10.824 7.571 ;
     RECT  7.8 6.371 8.112 7.957 ;
     RECT  9.36 7.093 9.384 7.957 ;
     RECT  7.8 7.957 9.384 9.637 ;
     RECT  12.144 6.709 12.168 9.875 ;
     RECT  13.2 2.151 13.512 10.165 ;
     RECT  18.6 7.237 19.752 10.213 ;
     RECT  13.2 10.165 13.752 11.365 ;
     RECT  12.24 11.365 13.752 11.459 ;
     RECT  7.392 9.637 9.384 11.797 ;
     RECT  6.864 11.797 9.384 11.893 ;
     RECT  6.864 11.893 9.528 11.941 ;
     RECT  6.864 11.941 9.96 11.987 ;
     RECT  18.6 10.213 19.896 12.035 ;
     RECT  9.504 11.987 9.96 12.949 ;
     RECT  12.24 11.459 13.512 13.045 ;
     RECT  9.12 12.949 9.96 13.235 ;
     RECT  11.376 13.045 13.512 13.285 ;
     RECT  11.376 13.285 13.656 13.715 ;
     RECT  12.24 13.715 13.656 16.259 ;
     RECT  0.192 14.869 0.216 16.355 ;
     RECT  6.864 11.987 8.112 16.595 ;
     RECT  9.936 13.235 9.96 16.595 ;
     RECT  16.224 13.813 16.248 16.595 ;
     RECT  18.6 12.035 18.912 18.181 ;
     RECT  6.72 17.989 6.744 19.379 ;
     RECT  7.8 16.595 8.112 19.861 ;
     RECT  15.552 18.757 15.576 19.907 ;
     RECT  16.704 19.909 16.728 20.339 ;
     RECT  15.264 21.781 15.288 22.165 ;
     RECT  18.288 18.181 18.912 22.165 ;
     RECT  7.8 19.861 8.232 22.741 ;
     RECT  15.264 22.165 15.384 22.835 ;
     RECT  18.192 22.165 18.912 23.027 ;
     RECT  7.8 22.741 9.096 23.077 ;
     RECT  13.2 16.259 13.656 23.171 ;
     RECT  15.312 22.835 15.384 23.171 ;
     RECT  7.8 23.077 10.008 23.557 ;
     RECT  7.8 23.557 10.488 23.893 ;
     RECT  7.8 23.893 11.256 25.715 ;
     RECT  10.464 25.715 11.256 25.861 ;
     RECT  13.2 23.171 13.512 26.341 ;
     RECT  13.104 26.341 13.512 26.531 ;
     RECT  13.2 26.531 13.512 26.629 ;
     RECT  9.456 25.715 9.48 26.725 ;
     RECT  10.464 25.861 11.592 26.725 ;
     RECT  7.8 25.715 8.472 26.819 ;
     RECT  9.456 26.725 11.592 27.157 ;
     RECT  9.12 27.157 11.592 27.829 ;
     RECT  15.312 23.171 15.336 27.877 ;
     RECT  14.832 27.877 15.336 27.923 ;
     RECT  14.832 27.923 14.856 28.211 ;
     RECT  13.2 26.629 13.656 28.357 ;
     RECT  7.8 26.819 8.112 29.221 ;
     RECT  9.12 27.829 11.832 29.365 ;
     RECT  13.2 28.357 13.848 29.365 ;
     RECT  7.392 29.221 8.112 30.611 ;
     RECT  9.12 29.365 13.848 30.611 ;
     RECT  9.12 30.611 13.512 31.379 ;
     RECT  12.672 31.379 13.512 31.667 ;
     RECT  7.8 30.611 8.112 31.669 ;
     RECT  9.12 31.379 11.064 31.669 ;
     RECT  2.4 2.151 2.712 32.409 ;
     RECT  7.8 31.669 11.064 32.409 ;
     RECT  13.2 31.667 13.512 32.409 ;
     RECT  18.6 23.027 18.912 32.409 ;
     RECT  24 2.151 24.312 32.409 ;
     RECT  29.4 2.151 29.712 32.409 ;
     RECT  34.8 2.151 35.112 32.409 ;
     RECT  40.2 2.151 40.512 32.409 ;
     RECT  2.4 32.409 2.52 32.423 ;
     RECT  7.8 32.409 7.92 32.423 ;
     RECT  13.2 32.409 13.32 32.423 ;
     RECT  18.6 32.409 18.72 32.423 ;
     RECT  24 32.409 24.12 32.423 ;
     RECT  29.4 32.409 29.52 32.423 ;
     RECT  34.8 32.409 34.92 32.423 ;
     RECT  40.2 32.409 40.32 32.423 ;
     RECT  9.024 32.409 11.064 33.733 ;
     RECT  9.024 33.733 11.208 34.384 ;
     RECT  9.048 1.811 10.176 2.291 ;
     RECT  7.92 2.137 9.024 2.151 ;
     RECT  11.184 6.275 11.208 6.709 ;
     RECT  8.112 6.371 8.232 7.093 ;
     RECT  11.184 6.709 12.144 7.429 ;
     RECT  12.168 6.709 13.2 9.875 ;
     RECT  8.112 7.093 9.36 7.957 ;
     RECT  9.384 7.429 10.8 7.571 ;
     RECT  10.824 7.429 12.144 7.571 ;
     RECT  12.24 9.875 13.2 11.365 ;
     RECT  8.112 11.987 9.504 12.949 ;
     RECT  8.112 12.949 9.12 13.235 ;
     RECT  9.96 13.045 11.376 13.715 ;
     RECT  6.864 16.595 7.8 17.989 ;
     RECT  6.744 17.989 7.8 19.379 ;
     RECT  8.472 25.715 9.456 26.819 ;
     RECT  9.48 25.715 10.464 26.725 ;
     RECT  11.592 26.341 13.104 26.531 ;
     RECT  11.592 26.531 13.2 27.829 ;
     RECT  8.112 26.819 9.456 27.157 ;
     RECT  8.112 27.157 9.12 31.669 ;
     RECT  11.832 27.829 13.2 29.365 ;
     RECT  13.656 27.877 14.832 28.211 ;
     RECT  13.656 28.211 13.848 28.357 ;
     RECT  7.92 32.409 9.024 32.423 ;
  END
END ot_s81_markov_mul_native
END LIBRARY
